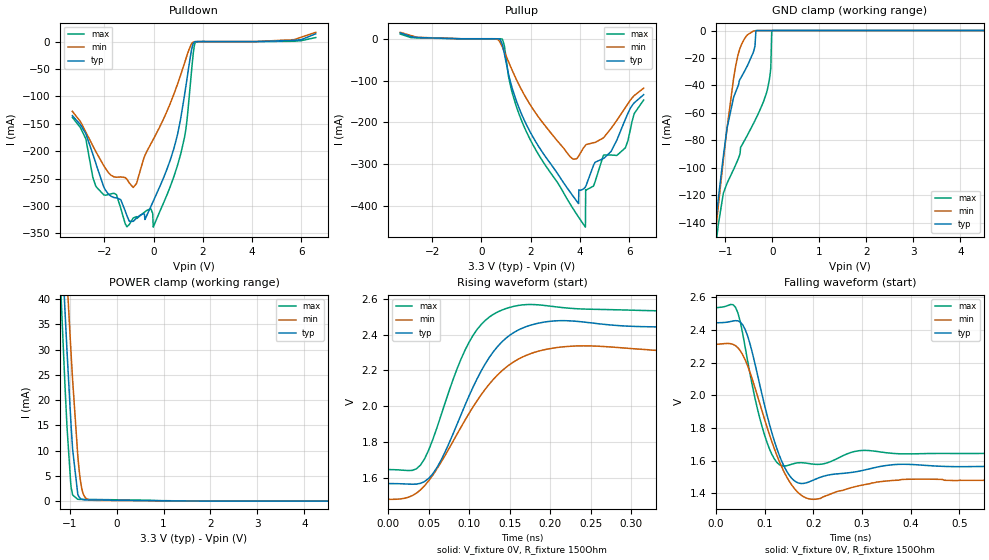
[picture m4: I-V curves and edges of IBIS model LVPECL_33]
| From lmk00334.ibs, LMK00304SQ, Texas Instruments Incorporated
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|   Model LVPECL_33
[Model]   LVPECL_33
Model_type   3-state
Polarity   Non-Inverting
Rref =   160.0000
Vmeas =   1.99
|   typ   min   max
|   Nom   Strong   Weak
C_comp   2.0749pF   1.9512pF   2.2734pF
|Output in low   Nom   Strong   Weak
|C_Comp   2.0749pF   1.9512pF   2.2734pF
|Output in High   Nom   Strong   Weak
|C_Comp   0.7651pF   0.6976pF   0.7651pF
[Voltage Range]   3.3   3.125   3.465
[Temperature Range]   45   125   -40
[Pullup Reference]   3.3   3.125   3.465
[Pulldown Reference]   0   0   -0
[Power Clamp Reference]   3.3   3.125   3.465
[GND Clamp Reference]   -0   -0   -0
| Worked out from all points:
|   slope of the pulldown table from 0 to 0.495 V, typ, clamps not added: 9.6 ohm
|   GND clamp passes 1 mA (typ) near -0.35 V on its own axis
|   POWER clamp passes 1 mA (typ) near -0.81 V on its own axis
|   falling waveform, V_fixture 0V, R_fixture 150Ohm: 20-80 % time 43.8ps typ, 54.1ps min, 37.3ps max; typ from 2.44 V to 1.57 V
|   rising waveform, V_fixture 0V, R_fixture 150Ohm: 20-80 % time 54ps typ, 68.8ps min, 43.9ps max; typ from 1.57 V to 2.44 V
[Pulldown]
|   Voltage   I(typ)   I(min)   I(max)
-3.3V     -135.3mA   -127.3mA   -138.3mA
-2.756V   -167.9mA   -164.8mA   -177.2mA
-2.35V    -221.3mA   -200.3mA   -263.5mA
-1.508V   -285.2mA   -247.5mA   -279.3mA
-1.082V   -317.8mA   -251.2mA   -338mA
-825mV    -328.1mA   -266.3mA   -322mA
-112.2mV  -301.3mA   -186.9mA   -305.6mA
-13.2mV   -291.4mA   -178.6mA   -338.6mA
1.115V    -137.3mA   -59.12mA   -203.1mA
1.313V    -81.64mA   -31.7mA    -160.1mA
1.7V      -291.1uA   -166.8uA   -1.54mA
6.59V     14.15mA    16.77mA    7.273mA
[GND Clamp]
|   Voltage   I(typ)   I(min)   I(max)
-3.3V     -1.043A    -996.1mA   -1.089A
-1.211V   -141.1mA   -147.5mA   -159.3mA
-1.162V   -126mA     -131.4mA   -144.5mA
-963.6mV  -70.9mA    -70.87mA   -111.2mA
-785.4mV  -45.14mA   -26.66mA   -98.18mA
-636.9mV  -32.43mA   -8.721mA   -82.8mA
-409.2mV  -16.23mA   -510.4uA   -68.24mA
-349.8mV  0A         -134.1uA   -64.14mA
-102.3mV  0A         -237.5nA   -42.45mA
-33mV     0A         -16.69nA   -26.95mA
-13.2mV   0A         -211.3pA   0A
6.59V     0A         0A         0A
[Pullup]
|   Voltage   I(typ)   I(min)   I(max)
-3.3V     13.99mA    15.2mA     11.16mA
858mV     -16.6mA    -20.98mA   -1.978mA
1.254V    -119.1mA   -76.24mA   -130.1mA
2.086V    -234.1mA   -167.4mA   -252.7mA
3.947V    -393.8mA   -280.5mA   -426.2mA
3.957V    -361.1mA   -279.5mA   -427mA
4.224V    -353.9mA   -254.8mA   -450.1mA
4.234V    -352.8mA   -254.2mA   -360.4mA
4.551V    -302.6mA   -248.5mA   -352mA
4.966V    -285.9mA   -236mA     -278.3mA
5.838V    -193.6mA   -165.4mA   -261.1mA
6.59V     -133.7mA   -118.2mA   -146.4mA
[POWER Clamp]
|   Voltage   I(typ)   I(min)   I(max)
-3.3V     591mA      563.1mA    632.3mA
-1.191V   56mA       69.05mA    42.73mA
-1.102V   38.65mA    52.49mA    23.91mA
-1.053V   29.47mA    43.66mA    14.46mA
-973.5mV  15.96mA    30.2mA     3.365mA
-933.9mV  10.18mA    23.88mA    1.219mA
-825mV    1.397mA    9.072mA    360.5uA
-775.5mV  581.4uA    4.543mA    346.4uA
-726mV    327.7uA    1.963mA    341.4uA
-666.6mV  254.2uA    731.6uA    336.4uA
-557.7mV  234.9uA    210uA      326.9uA
6.59V     0A         0A         0A
[Ramp]
R_load = 150
|   typ   min   max
dV/dt_r   0.526317/5.40378e-11   0.49711/6.86738e-11   0.534944/4.39459e-11
dV/dt_f   0.526301/4.37875e-11   0.497294/5.38573e-11   0.534789/3.73175e-11
[Falling Waveform]
V_fixture = 0V
V_fixture_min = 0V
V_fixture_max = 0V
R_fixture = 150Ohm
C_fixture = 0F
|   Time   V(typ)   V(min)   V(max)
0s        2.443V     2.311V     2.536V
40ps      2.456V     2.303V     2.538V
60ps      2.401V     2.216V     2.292V
100ps     1.936V     1.851V     1.755V
135ps     1.596V     1.561V     1.568V
165ps     1.469V     1.416V     1.585V
200ps     1.481V     1.363V     1.578V
295ps     1.536V     1.447V     1.661V
385ps     1.578V     1.485V     1.641V
1.36ns    1.566V     1.48V      1.644V
[Rising Waveform]
V_fixture = 0V
V_fixture_min = 0V
V_fixture_max = 0V
R_fixture = 150Ohm
C_fixture = 0F
|   Time   V(typ)   V(min)   V(max)
0s        1.566V     1.478V     1.645V
35ps      1.563V     1.513V     1.649V
55ps      1.62V      1.613V     1.811V
85ps      1.898V     1.843V     2.208V
105ps     2.109V     1.997V     2.398V
130ps     2.306V     2.151V     2.514V
160ps     2.425V     2.261V     2.563V
195ps     2.472V     2.318V     2.562V
240ps     2.471V     2.337V     2.543V
1.38ns    2.443V     2.309V     2.536V
